VERSION 5.7 ;
  NOWIREEXTENSIONATPIN ON ;
  DIVIDERCHAR "/" ;
  BUSBITCHARS "[]" ;
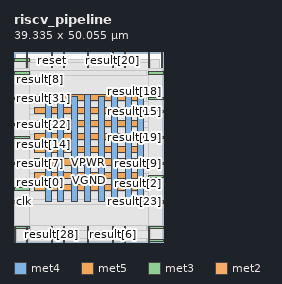
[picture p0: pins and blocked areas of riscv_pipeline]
MACRO riscv_pipeline
  CLASS BLOCK ;
  FOREIGN riscv_pipeline ;
  ORIGIN 0.000 0.000 ;
  SIZE 39.335 BY 50.055 ;
  PIN VGND
    DIRECTION INOUT ;
    USE GROUND ;
    PORT
      LAYER met4 ;
        RECT 11.525 10.640 13.125 38.760 ;
    END
    PORT
      LAYER met4 ;
        RECT 18.540 10.640 20.140 38.760 ;
    END
    PORT
      LAYER met4 ;
        RECT 25.555 10.640 27.155 38.760 ;
    END
    PORT
      LAYER met4 ;
        RECT 32.570 10.640 34.170 38.760 ;
    END
    PORT
      LAYER met5 ;
        RECT 5.280 16.775 34.170 18.375 ;
    END
    PORT
      LAYER met5 ;
        RECT 5.280 23.570 34.170 25.170 ;
    END
    PORT
      LAYER met5 ;
        RECT 5.280 30.365 34.170 31.965 ;
    END
    PORT
      LAYER met5 ;
        RECT 5.280 37.160 34.170 38.760 ;
    END
  END VGND
  PIN VPWR
    DIRECTION INOUT ;
    USE POWER ;
    PORT
      LAYER met4 ;
        RECT 8.225 10.640 9.825 38.320 ;
    END
    PORT
      LAYER met4 ;
        RECT 15.240 10.640 16.840 38.320 ;
    END
    PORT
      LAYER met4 ;
        RECT 22.255 10.640 23.855 38.320 ;
    END
    PORT
      LAYER met4 ;
        RECT 29.270 10.640 30.870 38.320 ;
    END
    PORT
      LAYER met5 ;
        RECT 5.280 13.475 33.820 15.075 ;
    END
    PORT
      LAYER met5 ;
        RECT 5.280 20.270 33.820 21.870 ;
    END
    PORT
      LAYER met5 ;
        RECT 5.280 27.065 33.820 28.665 ;
    END
    PORT
      LAYER met5 ;
        RECT 5.280 33.860 33.820 35.460 ;
    END
  END VPWR
  PIN clk
    DIRECTION INPUT ;
    USE SIGNAL ;
    PORT
      LAYER met3 ;
        RECT 0.000 10.240 4.000 10.840 ;
    END
  END clk
  PIN reset
    DIRECTION INPUT ;
    USE SIGNAL ;
    PORT
      LAYER met2 ;
        RECT 9.750 46.055 10.030 50.055 ;
    END
  END reset
  PIN result[0]
    DIRECTION OUTPUT TRISTATE ;
    USE SIGNAL ;
    PORT
      LAYER met3 ;
        RECT 0.000 13.640 4.000 14.240 ;
    END
  END result[0]
  PIN result[10]
    DIRECTION OUTPUT TRISTATE ;
    USE SIGNAL ;
    PORT
      LAYER met2 ;
        RECT 35.510 46.055 35.790 50.055 ;
    END
  END result[10]
  PIN result[11]
    DIRECTION OUTPUT TRISTATE ;
    USE SIGNAL ;
    PORT
      LAYER met3 ;
        RECT 0.000 47.640 4.000 48.240 ;
    END
  END result[11]
  PIN result[12]
    DIRECTION OUTPUT TRISTATE ;
    USE SIGNAL ;
    PORT
      LAYER met2 ;
        RECT 29.070 46.055 29.350 50.055 ;
    END
  END result[12]
  PIN result[13]
    DIRECTION OUTPUT TRISTATE ;
    USE SIGNAL ;
    PORT
      LAYER met3 ;
        RECT 0.000 3.440 4.000 4.040 ;
    END
  END result[13]
  PIN result[14]
    DIRECTION OUTPUT TRISTATE ;
    USE SIGNAL ;
    PORT
      LAYER met3 ;
        RECT 0.000 27.240 4.000 27.840 ;
    END
  END result[14]
  PIN result[15]
    DIRECTION OUTPUT TRISTATE ;
    USE SIGNAL ;
    PORT
      LAYER met3 ;
        RECT 35.335 34.040 39.335 34.640 ;
    END
  END result[15]
  PIN result[16]
    DIRECTION OUTPUT TRISTATE ;
    USE SIGNAL ;
    PORT
      LAYER met3 ;
        RECT 35.335 0.040 39.335 0.640 ;
    END
  END result[16]
  PIN result[17]
    DIRECTION OUTPUT TRISTATE ;
    USE SIGNAL ;
    PORT
      LAYER met2 ;
        RECT 35.510 0.000 35.790 4.000 ;
    END
  END result[17]
  PIN result[18]
    DIRECTION OUTPUT TRISTATE ;
    USE SIGNAL ;
    PORT
      LAYER met3 ;
        RECT 35.335 37.440 39.335 38.040 ;
    END
  END result[18]
  PIN result[19]
    DIRECTION OUTPUT TRISTATE ;
    USE SIGNAL ;
    PORT
      LAYER met3 ;
        RECT 35.335 27.240 39.335 27.840 ;
    END
  END result[19]
  PIN result[1]
    DIRECTION OUTPUT TRISTATE ;
    USE SIGNAL ;
    PORT
      LAYER met2 ;
        RECT 0.090 0.000 0.370 4.000 ;
    END
  END result[1]
  PIN result[20]
    DIRECTION OUTPUT TRISTATE ;
    USE SIGNAL ;
    PORT
      LAYER met2 ;
        RECT 25.850 46.055 26.130 50.055 ;
    END
  END result[20]
  PIN result[21]
    DIRECTION OUTPUT TRISTATE ;
    USE SIGNAL ;
    PORT
      LAYER met2 ;
        RECT 3.310 46.055 3.590 50.055 ;
    END
  END result[21]
  PIN result[22]
    DIRECTION OUTPUT TRISTATE ;
    USE SIGNAL ;
    PORT
      LAYER met3 ;
        RECT 0.000 30.640 4.000 31.240 ;
    END
  END result[22]
  PIN result[23]
    DIRECTION OUTPUT TRISTATE ;
    USE SIGNAL ;
    PORT
      LAYER met3 ;
        RECT 35.335 10.240 39.335 10.840 ;
    END
  END result[23]
  PIN result[24]
    DIRECTION OUTPUT TRISTATE ;
    USE SIGNAL ;
    PORT
      LAYER met2 ;
        RECT 29.070 0.000 29.350 4.000 ;
    END
  END result[24]
  PIN result[25]
    DIRECTION OUTPUT TRISTATE ;
    USE SIGNAL ;
    PORT
      LAYER met2 ;
        RECT 38.730 46.055 39.010 50.055 ;
    END
  END result[25]
  PIN result[26]
    DIRECTION OUTPUT TRISTATE ;
    USE SIGNAL ;
    PORT
      LAYER met3 ;
        RECT 35.335 3.440 39.335 4.040 ;
    END
  END result[26]
  PIN result[27]
    DIRECTION OUTPUT TRISTATE ;
    USE SIGNAL ;
    PORT
      LAYER met2 ;
        RECT 3.310 0.000 3.590 4.000 ;
    END
  END result[27]
  PIN result[28]
    DIRECTION OUTPUT TRISTATE ;
    USE SIGNAL ;
    PORT
      LAYER met2 ;
        RECT 9.750 0.000 10.030 4.000 ;
    END
  END result[28]
  PIN result[29]
    DIRECTION OUTPUT TRISTATE ;
    USE SIGNAL ;
    PORT
      LAYER met2 ;
        RECT 12.970 0.000 13.250 4.000 ;
    END
  END result[29]
  PIN result[2]
    DIRECTION OUTPUT TRISTATE ;
    USE SIGNAL ;
    PORT
      LAYER met3 ;
        RECT 35.335 17.040 39.335 17.640 ;
    END
  END result[2]
  PIN result[30]
    DIRECTION OUTPUT TRISTATE ;
    USE SIGNAL ;
    PORT
      LAYER met2 ;
        RECT 19.410 0.000 19.690 4.000 ;
    END
  END result[30]
  PIN result[31]
    DIRECTION OUTPUT TRISTATE ;
    USE SIGNAL ;
    PORT
      LAYER met3 ;
        RECT 0.000 37.440 4.000 38.040 ;
    END
  END result[31]
  PIN result[3]
    DIRECTION OUTPUT TRISTATE ;
    USE SIGNAL ;
    PORT
      LAYER met3 ;
        RECT 35.335 44.240 39.335 44.840 ;
    END
  END result[3]
  PIN result[4]
    DIRECTION OUTPUT TRISTATE ;
    USE SIGNAL ;
    PORT
      LAYER met2 ;
        RECT 12.970 46.055 13.250 50.055 ;
    END
  END result[4]
  PIN result[5]
    DIRECTION OUTPUT TRISTATE ;
    USE SIGNAL ;
    PORT
      LAYER met2 ;
        RECT 19.410 46.055 19.690 50.055 ;
    END
  END result[5]
  PIN result[6]
    DIRECTION OUTPUT TRISTATE ;
    USE SIGNAL ;
    PORT
      LAYER met2 ;
        RECT 25.850 0.000 26.130 4.000 ;
    END
  END result[6]
  PIN result[7]
    DIRECTION OUTPUT TRISTATE ;
    USE SIGNAL ;
    PORT
      LAYER met3 ;
        RECT 0.000 20.440 4.000 21.040 ;
    END
  END result[7]
  PIN result[8]
    DIRECTION OUTPUT TRISTATE ;
    USE SIGNAL ;
    PORT
      LAYER met3 ;
        RECT 0.000 44.240 4.000 44.840 ;
    END
  END result[8]
  PIN result[9]
    DIRECTION OUTPUT TRISTATE ;
    USE SIGNAL ;
    PORT
      LAYER met3 ;
        RECT 35.335 20.440 39.335 21.040 ;
    END
  END result[9]
  OBS
      LAYER li1 ;
        RECT 5.520 10.795 33.580 38.165 ;
      LAYER met1 ;
        RECT 0.070 10.640 39.030 38.320 ;
      LAYER met2 ;
        RECT 0.100 45.775 3.030 48.125 ;
        RECT 3.870 45.775 9.470 48.125 ;
        RECT 10.310 45.775 12.690 48.125 ;
        RECT 13.530 45.775 19.130 48.125 ;
        RECT 19.970 45.775 25.570 48.125 ;
        RECT 26.410 45.775 28.790 48.125 ;
        RECT 29.630 45.775 35.230 48.125 ;
        RECT 36.070 45.775 38.450 48.125 ;
        RECT 0.100 4.280 39.000 45.775 ;
        RECT 0.650 0.155 3.030 4.280 ;
        RECT 3.870 0.155 9.470 4.280 ;
        RECT 10.310 0.155 12.690 4.280 ;
        RECT 13.530 0.155 19.130 4.280 ;
        RECT 19.970 0.155 25.570 4.280 ;
        RECT 26.410 0.155 28.790 4.280 ;
        RECT 29.630 0.155 35.230 4.280 ;
        RECT 36.070 0.155 39.000 4.280 ;
      LAYER met3 ;
        RECT 4.400 47.240 35.335 48.105 ;
        RECT 4.000 45.240 35.335 47.240 ;
        RECT 4.400 43.840 34.935 45.240 ;
        RECT 4.000 38.440 35.335 43.840 ;
        RECT 4.400 37.040 34.935 38.440 ;
        RECT 4.000 35.040 35.335 37.040 ;
        RECT 4.000 33.640 34.935 35.040 ;
        RECT 4.000 31.640 35.335 33.640 ;
        RECT 4.400 30.240 35.335 31.640 ;
        RECT 4.000 28.240 35.335 30.240 ;
        RECT 4.400 26.840 34.935 28.240 ;
        RECT 4.000 21.440 35.335 26.840 ;
        RECT 4.400 20.040 34.935 21.440 ;
        RECT 4.000 18.040 35.335 20.040 ;
        RECT 4.000 16.640 34.935 18.040 ;
        RECT 4.000 14.640 35.335 16.640 ;
        RECT 4.400 13.240 35.335 14.640 ;
        RECT 4.000 11.240 35.335 13.240 ;
        RECT 4.400 9.840 34.935 11.240 ;
        RECT 4.000 4.440 35.335 9.840 ;
        RECT 4.400 3.040 34.935 4.440 ;
        RECT 4.000 1.040 35.335 3.040 ;
        RECT 4.000 0.175 34.935 1.040 ;
  END
END riscv_pipeline
END LIBRARY

